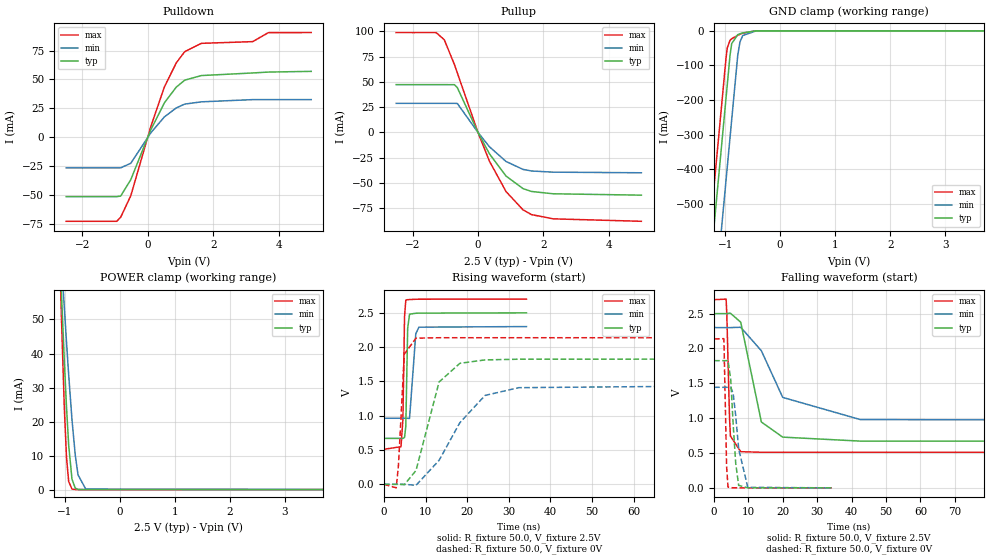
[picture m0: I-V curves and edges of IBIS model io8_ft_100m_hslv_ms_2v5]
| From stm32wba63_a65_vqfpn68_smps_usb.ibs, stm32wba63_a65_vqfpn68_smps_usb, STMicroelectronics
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[Model]   io8_ft_100m_hslv_ms_2v5
Model_type I/O
Polarity   Non-Inverting
Enable   Active-Low
| CAP_THRESHOLD on pad IOFT is "UDTCAPC" :
| Rising=30.0% of vddiom   Falling=70.0% of vddiom
| C_comp min and max val. don't necessarily correlate with the min and max pvt
| but are the smallest and greatest pad capacitance found.
| var   typ   min   max
C_comp   3.76253pF  3.70188pF  3.88980pF
|C_comp_pullup   2.23740pF  2.13186pF  2.39660pF
|C_comp_pulldown   1.52513pF  1.57002pF  1.49320pF
Vinl = 1.15V
Vinh = 1.35V
Vmeas = 1.25V   | Reference voltage for timing measurements
Cref  = 50.0pF   | Timing specification test load capacitance value
Rref  = 1.0MOhm   | Timing specification test load resistance value
Vref  = 1.375V   | Timing specification test load voltage
[Model Spec]
| TIME_THRESHOLD on pin ZIV11 is "CMOS" :
| Rising=50.0% of vdd   Falling=50.0% of vdd
Vinl 992.50000mV 921.50000mV 1.05850V
Vinh 1.43350V 1.32250V 1.51250V
| variable   typ   min   max
[Temperature Range] 25.0 140.0 -40.0
| variable   typ   min   max
[Voltage Range] 2.5V 2.3V 2.7V
| variable   typ   min   max
[POWER Clamp Reference] 2.5V 2.3V 2.7V
| variable   typ   min   max
[GND Clamp Reference] 0V 0V 0V
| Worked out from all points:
|   slope of the pulldown table from 0 to 0.375 V, typ, clamps not added: 16.2 ohm
|   slope of the pullup table from 0 to 0.375 V, typ, clamps not added: 16.7 ohm
|   GND clamp passes 1 mA (typ) near -0.51 V on its own axis
|   POWER clamp passes 1 mA (typ) near -0.83 V on its own axis
|   rising waveform, R_fixture 50.0, V_fixture 2.5V: 20-80 % time 286ps typ, 439ps min, 348ps max; typ from 0.67 V to 2.5 V
|   falling waveform, R_fixture 50.0, V_fixture 2.5V: 20-80 % time 4.27ns typ, 8.39ns min, 708ps max; typ from 2.5 V to 0.67 V
|   rising waveform, R_fixture 50.0, V_fixture 0V: 20-80 % time 4.57ns typ, 8.63ns min, 1ns max; typ from 0 V to 1.82 V
|   falling waveform, R_fixture 50.0, V_fixture 0V: 20-80 % time 1.28ns typ, 1.83ns min, 497ps max; typ from 1.82 V to 0 V
[POWER Clamp]
-2.5V     733.7mA    502.6mA    1.062A
-1.09V    69.42mA    75.17mA    67.14mA
-1.08V    65.31mA    72.42mA    61.23mA
-1.06V    57.23mA    66.98mA    49.77mA
-1.01V    38.06mA    53.68mA    24.29mA
-970mV    24.36mA    43.46mA    9.575mA
-930mV    13.06mA    33.74mA    2.352mA
-870mV    3.065mA    20.56mA    165.9uA
-810mV    418.4uA    10.06mA    10.3uA
-760mV    69.41uA    4.321mA    1.008uA
-620mV    424.8nA    151.9uA    1.655nA
5V        0A         0A         0A
[GND Clamp]
-2.5V     -2.774A    -3.011A    -2.658A
-1.45V    -988.6mA   -1.226A    -873.4mA
-1.21V    -580.6mA   -818.3mA   -465.4mA
-980mV    -189.6mA   -427.3mA   -74.41mA
-960mV    -155.6mA   -393.3mA   -49.14mA
-910mV    -70.61mA   -308.3mA   -27.43mA
-880mV    -37.05mA   -257.3mA   -22.95mA
-770mV    -11.2mA    -71.03mA   -13.02mA
-730mV    -8.651mA   -32.36mA   -10.11mA
-680mV    -6.129mA   -13.76mA   -6.945mA
-450mV    -356.3uA   -840.3uA   -213.1uA
5V        1.758nA    357.7nA    738.1pA
| variable   typ   min   max
[Pullup Reference] 2.5V 2.3V 2.7V
| variable   typ   min   max
[Pulldown Reference] 0V 0V 0V
[Pullup]
-2.5V     47.26mA    28.72mA    98.9mA
-1.28V    47.26mA    28.72mA    98.89mA
-1.03V    47.26mA    28.72mA    91.82mA
-720mV    47.21mA    28.72mA    67.31mA
-630mV    44.31mA    28.56mA    58.9mA
0V        692.6fA    264.9pA    3.85fA
350mV     -21.24mA   -14.26mA   -28.5mA
860mV     -43.37mA   -28.93mA   -58.75mA
1.38V     -55.84mA   -36.8mA    -76.9mA
1.64V     -58.66mA   -38.36mA   -81.62mA
2.3V      -60.96mA   -39.52mA   -85.81mA
5V        -62.33mA   -40.13mA   -88.25mA
[Pulldown]
-2.5V     -51.61mA   -26.66mA   -73.01mA
-950mV    -51.61mA   -26.66mA   -73.01mA
-830mV    -51.13mA   -26.66mA   -69.5mA
-520mV    -36.86mA   -22.67mA   -50.81mA
90mV      6.214mA    3.696mA    8.997mA
510mV     29.86mA    17.62mA    43.74mA
870mV     43.36mA    25.34mA    64.34mA
1.13V     49.44mA    28.66mA    74.15mA
1.64V     53.42mA    30.62mA    81.36mA
3.21V     55.67mA    32.54mA    82.85mA
3.69V     56.44mA    32.54mA    90.68mA
5V        57.06mA    32.54mA    90.71mA
[Ramp]
dV/dt_r 1.09519V/4.52368ns 865.96463mV/8.50295ns 1.28201V/1.00176ns
dV/dt_f 1.09819V/4.07032ns 802.23125mV/8.03883ns 1.31366V/706.60976ps
R_load = 50.0
| Removed startup time: 0s 0s 0s  .
| Removed end time: 34.25ns.
[Rising Waveform]
R_fixture   = 50.0
V_fixture   = 2.5V
V_fixture_min = 2.3V
V_fixture_max = 2.7V
0s        669.7mV    962.9mV    510.6mV
4.1ns     669.7mV    963mV      548.1mV
4.55ns    668.5mV    963mV      941mV
4.95ns    684.3mV    963mV      2.448V
5.25ns    842mV      963mV      2.685V
5.7ns     2.272V     962.6mV    2.692V
6.15ns    2.48V      959.9mV    2.694V
7.65ns    2.494V     2.194V     2.698V
8.4ns     2.496V     2.291V     2.699V
34.25ns   2.5V       2.3V       2.7V
| Removed startup time: 0s 0s 0s  .
| Removed end time: 189.25ns.
[Falling Waveform]
R_fixture   = 50.0
V_fixture   = 2.5V
V_fixture_min = 2.3V
V_fixture_max = 2.7V
0s        2.5V       2.3V       2.7V
3.5ns     2.5V       2.3V       2.708V
3.7ns     2.5V       2.3V       2.494V
4.5ns     2.506V     2.3V       994.7mV
4.75ns    2.506V     2.3V       743.8mV
7.75ns    2.377V     2.304V     519.1mV
13.75ns   944.8mV    1.967V     510.7mV
19.95ns   728mV      1.298V     510.6mV
42.5ns    670.8mV    980mV      510.6mV
189.3ns   669.7mV    962.9mV    510.6mV
| Removed startup time: 0s 0s 0s  .
| Removed end time: 99.2ns.
[Rising Waveform]
R_fixture   = 50.0
V_fixture   = 0V
V_fixture_min = 0V
V_fixture_max = 0V
0s        5.305nV    128.7nV    4.668nV
2.95ns    4.621uV    240.2nV    -51.85mV
3.5ns     3.598uV    5.207uV    287.6mV
4.9ns     -5.327mV   490.9nV    1.899V
7.7ns     200.8mV    -14.78mV   2.131V
13.25ns   1.492V     349.8mV    2.137V
18.25ns   1.764V     899.4mV    2.137V
24.3ns    1.814V     1.296V     2.137V
32.4ns    1.824V     1.409V     2.137V
99.2ns    1.825V     1.443V     2.137V
| Removed startup time: 0s 0s 0s  .
| Removed end time: 34.2ns.
[Falling Waveform]
R_fixture   = 50.0
V_fixture   = 0V
V_fixture_min = 0V
V_fixture_max = 0V
0s        1.825V     1.443V     2.137V
2.85ns    1.825V     1.443V     2.141V
3.65ns    1.825V     1.443V     301.9mV
4.05ns    1.83V      1.443V     10.34mV
4.85ns    1.55V      1.444V     2.276mV
5.55ns    912.6mV    1.357V     1.521mV
6.3ns     346.1mV    1.03V      945.5uV
7.15ns    35.78mV    559.4mV    548.6uV
9.8ns     1.531mV    7.24mV     107.7uV
34.2ns    19.87uV    103uV      22.06nV
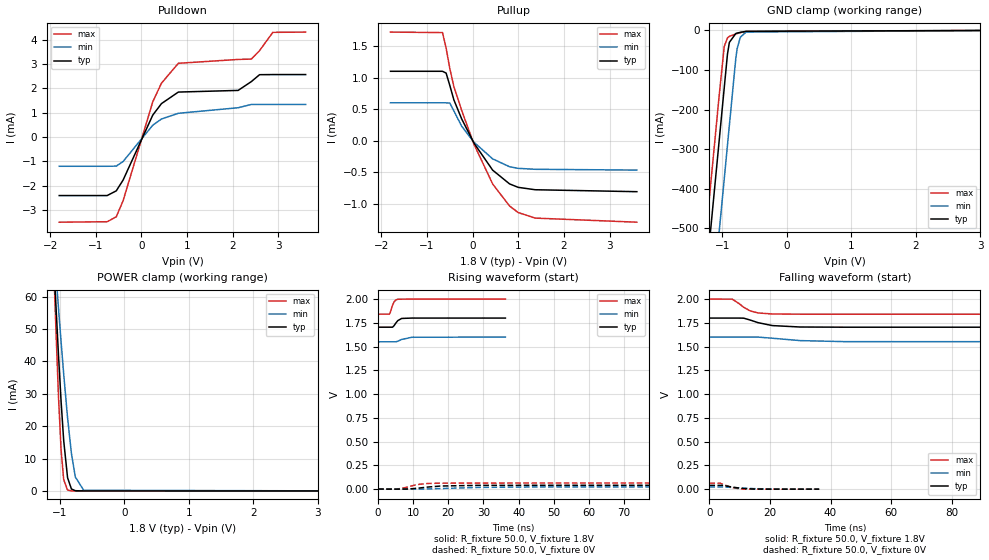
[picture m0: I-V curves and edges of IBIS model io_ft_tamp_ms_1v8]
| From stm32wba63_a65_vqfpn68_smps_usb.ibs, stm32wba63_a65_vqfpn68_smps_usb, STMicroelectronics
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[Model]   io_ft_tamp_ms_1v8
Model_type I/O
Polarity   Non-Inverting
Enable   Active-Low
| CAP_THRESHOLD on pad IOFT is "UDTCAPC" :
| Rising=30.0% of vddios   Falling=70.0% of vddios
| C_comp min and max val. don't necessarily correlate with the min and max pvt
| but are the smallest and greatest pad capacitance found.
| var   typ   min   max
C_comp   2.65322pF  2.64172pF  2.73746pF
|C_comp_pullup   1.56708pF  1.50789pF  1.65254pF
|C_comp_pulldown   1.08614pF  1.13383pF  1.08492pF
Vinl = 800.0mV
Vinh = 1.0V
Vmeas = 900.0mV   | Reference voltage for timing measurements
Cref  = 50.0pF   | Timing specification test load capacitance value
Rref  = 1.0MOhm   | Timing specification test load resistance value
Vref  = 990.0mV   | Timing specification test load voltage
[Model Spec]
| TIME_THRESHOLD on pin ZIV11 is "CMOS" :
| Rising=50.0% of vdd   Falling=50.0% of vdd
Vinl 702.50000mV 626.50000mV 788.50000mV
Vinh 1.09050V 959.50000mV 1.19650V
| variable   typ   min   max
[Temperature Range] 25.0 140.0 -40.0
| variable   typ   min   max
[Voltage Range] 1.8V 1.6V 2.0V
| variable   typ   min   max
[POWER Clamp Reference] 1.8V 1.6V 2.0V
| variable   typ   min   max
[GND Clamp Reference] 0V 0V 0V
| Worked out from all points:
|   slope of the pulldown table from 0 to 0.27 V, typ, clamps not added: 284 ohm
|   slope of the pullup table from 0 to 0.27 V, typ, clamps not added: 860 ohm
|   GND clamp passes 1 mA (typ) near -0.54 V on its own axis
|   POWER clamp passes 1 mA (typ) near -0.83 V on its own axis
|   rising waveform, R_fixture 50.0, V_fixture 1.8V: 20-80 % time 1.23ns typ, NA min, 931ps max; typ from 1.7 V to 1.8 V
|   falling waveform, R_fixture 50.0, V_fixture 1.8V: 20-80 % time 6.82ns typ, NA min, 4.68ns max; typ from 1.8 V to 1.7 V
[POWER Clamp]
-1.8V     396.4mA    285.5mA    556.9mA
-1.09V    69.42mA    75.17mA    67.14mA
-1.08V    65.31mA    72.42mA    61.23mA
-1.06V    57.23mA    66.98mA    49.77mA
-1.02V    41.75mA    56.3mA     28.91mA
-980mV    27.6mA     45.97mA    12.6mA
-940mV    15.59mA    36.11mA    3.485mA
-880mV    4.091mA    22.61mA    262.5uA
-820mV    594.6uA    11.56mA    16.39uA
-760mV    69.41uA    4.321mA    1.008uA
-630mV    610.8nA    197uA      2.464nA
3.6V      0A         0A         0A
[GND Clamp]
-1.8V     -1.557A    -1.787A    -1.443A
-1.33V    -757.8mA   -987.8mA   -644.3mA
-1.24V    -604.8mA   -834.8mA   -491.3mA
-1.05V    -281.8mA   -511.8mA   -168.3mA
-970mV    -145.8mA   -375.8mA   -41.09mA
-920mV    -60.82mA   -290.8mA   -19.19mA
-890mV    -30.35mA   -239.8mA   -15.35mA
-790mV    -8.023mA   -70.37mA   -9.131mA
-770mV    -6.967mA   -46.42mA   -8.145mA
-720mV    -5.017mA   -17.37mA   -5.895mA
-630mV    -2.538mA   -4.268mA   -2.717mA
3.6V      1.094nA    260.9nA    370.3pA
| variable   typ   min   max
[Pullup Reference] 1.8V 1.6V 2.0V
| variable   typ   min   max
[Pulldown Reference] 0V 0V 0V
[Pullup]
-1.8V     1.102mA    600.9uA    1.725mA
-660mV    1.102mA    600.9uA    1.717mA
-580mV    1.073mA    600.9uA    1.471mA
-500mV    878.6uA    596.9uA    1.148mA
-410mV    647uA      473uA      857.3uA
-240mV    346.5uA    229.5uA    481.9uA
30mV      -39.57uA   -24.87uA   -57.04uA
440mV     -469.3uA   -290.3uA   -689.6uA
810mV     -687.5uA   -414.5uA   -1.039mA
1V        -742.5uA   -440.4uA   -1.143mA
1.37V     -780.2uA   -455.3uA   -1.231mA
3.6V      -811.3uA   -468.1uA   -1.296mA
[Pulldown]
-1.8V     -2.401mA   -1.198mA   -3.493mA
-750mV    -2.4mA     -1.198mA   -3.474mA
-550mV    -2.207mA   -1.193mA   -3.271mA
-400mV    -1.763mA   -1.002mA   -2.612mA
250mV     901.5uA    487.8uA    1.448mA
440mV     1.372mA    740.5uA    2.21mA
810mV     1.846mA    975.4uA    3.026mA
2.12V     1.914mA    1.203mA    3.185mA
2.41V     2.276mA    1.339mA    3.199mA
2.59V     2.559mA    1.339mA    3.547mA
2.88V     2.564mA    1.339mA    4.296mA
3.6V      2.564mA    1.339mA    4.307mA
[Ramp]
dV/dt_r 23.80737mV/6.72707ns 13.765mV/12.36018ns 38.01799mV/4.31875ns
dV/dt_f 57.33012mV/6.78903ns 29.81528mV/11.52238ns 95.55841mV/4.6523ns
R_load = 50.0
| Removed startup time: 0s 0s 0s  .
| Removed end time: 36.25ns.
[Rising Waveform]
R_fixture   = 50.0
V_fixture   = 1.8V
V_fixture_min = 1.6V
V_fixture_max = 2.0V
0s        1.704V     1.55V      1.841V
3.2ns     1.704V     1.55V      1.841V
3.45ns    1.704V     1.55V      1.859V
4.1ns     1.704V     1.55V      1.935V
4.5ns     1.718V     1.55V      1.968V
5ns       1.745V     1.55V      1.99V
5.6ns     1.773V     1.556V     1.998V
6.7ns     1.796V     1.575V     1.999V
9.65ns    1.8V       1.598V     2V
36.25ns   1.8V       1.6V       2V
| Removed startup time: 0s 0s 0s  .
| Removed end time: 199.25ns.
[Falling Waveform]
R_fixture   = 50.0
V_fixture   = 1.8V
V_fixture_min = 1.6V
V_fixture_max = 2.0V
0s        1.8V       1.6V       2V
7.55ns    1.8V       1.6V       1.999V
9.75ns    1.8V       1.6V       1.954V
11.35ns   1.799V     1.6V       1.913V
13.5ns    1.779V     1.6V       1.875V
16.05ns   1.752V     1.6V       1.854V
20.8ns    1.721V     1.588V     1.843V
29.95ns   1.706V     1.563V     1.841V
44.75ns   1.704V     1.552V     1.841V
199.3ns   1.704V     1.55V      1.841V
| Removed startup time: 0s 0s 0s  .
| Removed end time: 199.25ns.
[Rising Waveform]
R_fixture   = 50.0
V_fixture   = 0V
V_fixture_min = 0V
V_fixture_max = 0V
0s        14.23nV    329.4nV    13.51nV
5.25ns    -1mV       -295.2uV   -831.1uV
7.95ns    413.7uV    -471.3uV   16.89mV
10.15ns   5.226mV    -281.2uV   39.19mV
11.75ns   11.05mV    238.3uV    50.52mV
14.15ns   21.18mV    1.427mV    58.85mV
17.85ns   32.09mV    5.361mV    62.47mV
28.45ns   39.25mV    17.55mV    63.33mV
44.75ns   39.66mV    22.41mV    63.35mV
199.3ns   39.68mV    22.94mV    63.36mV
| Removed startup time: 0s 0s 0s  .
| Removed end time: 36.25ns.
[Falling Waveform]
R_fixture   = 50.0
V_fixture   = 0V
V_fixture_min = 0V
V_fixture_max = 0V
0s        39.68mV    22.95mV    63.37mV
3.5ns     39.67mV    22.94mV    63.2mV
4.55ns    39.3mV     22.94mV    50.45mV
6.65ns    27.14mV    20.11mV    24.93mV
7.45ns    22.79mV    18.41mV    16.82mV
9.35ns    13.47mV    14.58mV    6.781mV
11.1ns    7.25mV     11.34mV    1.394mV
14.8ns    1.133mV    5.582mV    203.2uV
21.5ns    113.6uV    911.1uV    20.25uV
36.25ns   3.625uV    42.75uV    87.42nV
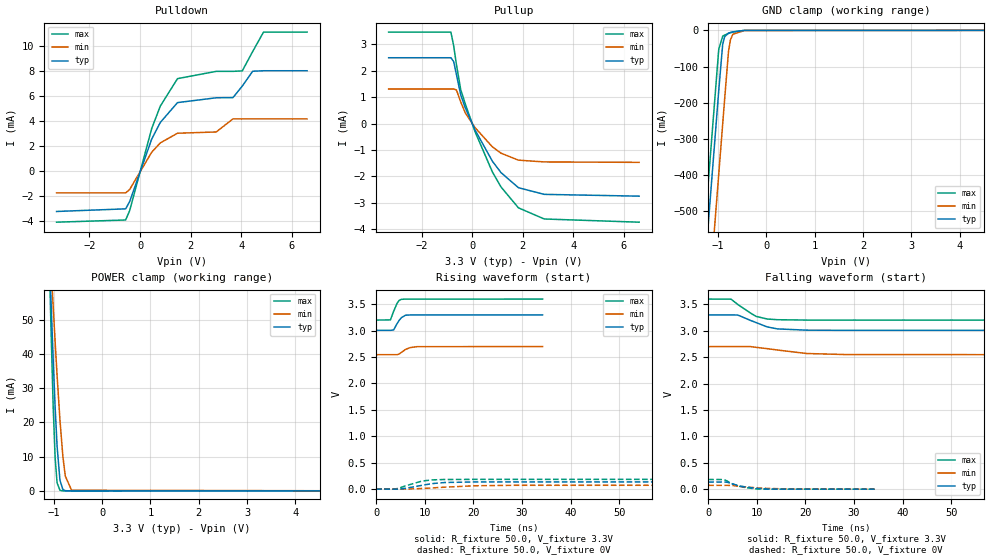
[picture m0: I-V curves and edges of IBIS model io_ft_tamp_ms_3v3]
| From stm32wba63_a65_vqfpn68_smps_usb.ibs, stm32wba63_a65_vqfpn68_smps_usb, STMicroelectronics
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[Model]   io_ft_tamp_ms_3v3
Model_type I/O
Polarity   Non-Inverting
Enable   Active-Low
| CAP_THRESHOLD on pad IOFT is "UDTCAPC" :
| Rising=30.0% of vddios   Falling=70.0% of vddios
| C_comp min and max val. don't necessarily correlate with the min and max pvt
| but are the smallest and greatest pad capacitance found.
| var   typ   min   max
C_comp   2.93634pF  2.87256pF  2.96827pF
|C_comp_pullup   1.79794pF  1.68457pF  1.83935pF
|C_comp_pulldown   1.13840pF  1.18799pF  1.12892pF
Vinl = 1.35V
Vinh = 1.8V
Vmeas = 1.65V   | Reference voltage for timing measurements
Cref  = 50.0pF   | Timing specification test load capacitance value
Rref  = 1.0MOhm   | Timing specification test load resistance value
Vref  = 1.815V   | Timing specification test load voltage
[Model Spec]
| TIME_THRESHOLD on pin ZIV11 is "CMOS" :
| Rising=50.0% of vdd   Falling=50.0% of vdd
Vinl 1.29050V 1.08050V 1.37650V
Vinh 1.79850V 1.52050V 1.90250V
| variable   typ   min   max
[Temperature Range] 25.0 140.0 -40.0
| variable   typ   min   max
[Voltage Range] 3.3V 2.7V 3.6V
| variable   typ   min   max
[POWER Clamp Reference] 3.3V 2.7V 3.6V
| variable   typ   min   max
[GND Clamp Reference] 0V 0V 0V
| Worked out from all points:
|   slope of the pulldown table from 0 to 0.495 V, typ, clamps not added: 186 ohm
|   slope of the pullup table from 0 to 0.495 V, typ, clamps not added: 523 ohm
|   GND clamp passes 1 mA (typ) near -0.54 V on its own axis
|   POWER clamp passes 1 mA (typ) near -0.83 V on its own axis
|   rising waveform, R_fixture 50.0, V_fixture 3.3V: 20-80 % time 1.19ns typ, 1.64ns min, 1.04ns max; typ from 3.01 V to 3.3 V
|   falling waveform, R_fixture 50.0, V_fixture 3.3V: 20-80 % time 4.92ns typ, 7.75ns min, 3.9ns max; typ from 3.3 V to 3.01 V
|   rising waveform, R_fixture 50.0, V_fixture 0V: 20-80 % time 5.11ns typ, 8.57ns min, 3.85ns max; typ from 0 V to 0.135 V
|   falling waveform, R_fixture 50.0, V_fixture 0V: 20-80 % time 3.95ns typ, 6.17ns min, 3.12ns max; typ from 0.135 V to 0 V
[POWER Clamp]
-3.3V     1.123A     753mA      1.645A
-1.09V    69.42mA    75.17mA    67.14mA
-1.08V    65.31mA    72.42mA    61.23mA
-1.06V    57.23mA    66.98mA    49.77mA
-1.01V    38.06mA    53.68mA    24.29mA
-970mV    24.36mA    43.46mA    9.575mA
-930mV    13.06mA    33.74mA    2.352mA
-870mV    3.065mA    20.56mA    165.9uA
-810mV    418.4uA    10.06mA    10.3uA
-760mV    69.41uA    4.321mA    1.008uA
-630mV    611nA      197uA      2.689nA
6.6V      0A         0A         0A
[GND Clamp]
-3.3V     -4.108A    -4.338A    -3.993A
-1.47V    -996.5mA   -1.227A    -882.1mA
-1.25V    -622.5mA   -853.4mA   -508.1mA
-990mV    -180.5mA   -411.4mA   -66.09mA
-980mV    -163.5mA   -394.4mA   -51.42mA
-900mV    -38.37mA   -258.4mA   -16.28mA
-860mV    -17.66mA   -190.4mA   -13.03mA
-780mV    -7.657mA   -58.45mA   -8.63mA
-740mV    -5.866mA   -26.35mA   -6.764mA
-690mV    -4.176mA   -10.78mA   -4.712mA
-450mV    -220.4uA   -529.3uA   -129.7uA
6.6V      1.984nA    498.7nA    735.2pA
| variable   typ   min   max
[Pullup Reference] 3.3V 2.7V 3.6V
| variable   typ   min   max
[Pulldown Reference] 0V 0V 0V
[Pullup]
-3.3V     2.485mA    1.306mA    3.454mA
-840mV    2.485mA    1.306mA    3.454mA
-730mV    2.34mA     1.306mA    2.94mA
-620mV    1.848mA    1.267mA    2.224mA
-450mV    1.076mA    812.1uA    1.276mA
-270mV    593.3uA    399.8uA    738.7uA
120mV     -251.9uA   -160.4uA   -321uA
800mV     -1.423mA   -878.8uA   -1.828mA
1.14V     -1.853mA   -1.12mA    -2.394mA
1.83V     -2.424mA   -1.383mA   -3.184mA
2.85V     -2.675mA   -1.45mA    -3.605mA
6.6V      -2.743mA   -1.466mA   -3.726mA
[Pulldown]
-3.3V     -3.274mA   -1.782mA   -4.133mA
-570mV    -3.064mA   -1.782mA   -3.957mA
-410mV    -2.48mA    -1.511mA   -3.207mA
460mV     2.522mA    1.473mA    3.369mA
800mV     3.858mA    2.222mA    5.168mA
1.48V     5.45mA     2.995mA    7.37mA
3.01V     5.836mA    3.097mA    7.954mA
3.67V     5.848mA    4.142mA    7.954mA
4.04V     6.772mA    4.142mA    7.991mA
4.45V     7.963mA    4.142mA    9.539mA
4.88V     8.002mA    4.142mA    11.1mA
6.6V      8.002mA    4.142mA    11.1mA
[Ramp]
dV/dt_r 80.90713mV/5.10638ns 43.29886mV/8.49108ns 109.86911mV/3.85346ns
dV/dt_f 175.10509mV/4.91333ns 92.30532mV/7.62111ns 238.66584mV/3.88874ns
R_load = 50.0
| Removed startup time: 0s 0s 0s  .
| Removed end time: 34.25ns.
[Rising Waveform]
R_fixture   = 50.0
V_fixture   = 3.3V
V_fixture_min = 2.7V
V_fixture_max = 3.6V
0s        3.008V     2.546V     3.202V
2.95ns    3.008V     2.546V     3.205V
3.6ns     3.013V     2.546V     3.367V
4.3ns     3.133V     2.546V     3.517V
4.75ns    3.197V     2.558V     3.576V
5.2ns     3.248V     2.59V      3.595V
6.05ns    3.294V     2.645V     3.599V
7ns       3.299V     2.68V      3.599V
8.4ns     3.299V     2.698V     3.599V
34.25ns   3.3V       2.7V       3.6V
| Removed startup time: 0s 0s 0s  .
| Removed end time: 99.25ns.
[Falling Waveform]
R_fixture   = 50.0
V_fixture   = 3.3V
V_fixture_min = 2.7V
V_fixture_max = 3.6V
0s        3.3V       2.7V       3.6V
4.7ns     3.301V     2.7V       3.598V
6.1ns     3.297V     2.7V       3.497V
8.7ns     3.196V     2.7V       3.335V
9.85ns    3.155V     2.686V     3.272V
12.15ns   3.072V     2.661V     3.222V
14.25ns   3.035V     2.635V     3.209V
20.25ns   3.011V     2.569V     3.202V
28.35ns   3.008V     2.549V     3.202V
99.25ns   3.008V     2.546V     3.202V
| Removed startup time: 0s 0s 0s  .
| Removed end time: 99.25ns.
[Rising Waveform]
R_fixture   = 50.0
V_fixture   = 0V
V_fixture_min = 0V
V_fixture_max = 0V
0s        79.54nV    353.3nV    261.5nV
3.85ns    -2.551mV   23.18uV    -1.031mV
4.7ns     -1.673mV   -1.157mV   16.63mV
6ns       13.22mV    -1.288mV   58.3mV
9.4ns     69.43mV    10.18mV    150.7mV
11.5ns    102.6mV    20.66mV    173.1mV
14.15ns   123.8mV    35.37mV    180.8mV
20.25ns   134mV      61.92mV    183mV
28.35ns   134.8mV    70.75mV    183.1mV
99.25ns   134.8mV    72.17mV    183.1mV
| Removed startup time: 0s 0s 0s  .
| Removed end time: 34.25ns.
[Falling Waveform]
R_fixture   = 50.0
V_fixture   = 0V
V_fixture_min = 0V
V_fixture_max = 0V
0s        134.9mV    72.18mV    183.1mV
3.2ns     134.8mV    72.18mV    181.9mV
3.9ns     131.7mV    72.15mV    155.4mV
5.05ns    100.7mV    68.93mV    94.12mV
6.1ns     68.82mV    58.18mV    60.85mV
7.7ns     40.11mV    42.22mV    28.23mV
10.05ns   14.78mV    24.82mV    3.164mV
12.6ns    1.251mV    13.34mV    297.7uV
17.5ns    112.3uV    1.2mV      28.98uV
34.25ns   334nV      10.44uV    352.1nV
